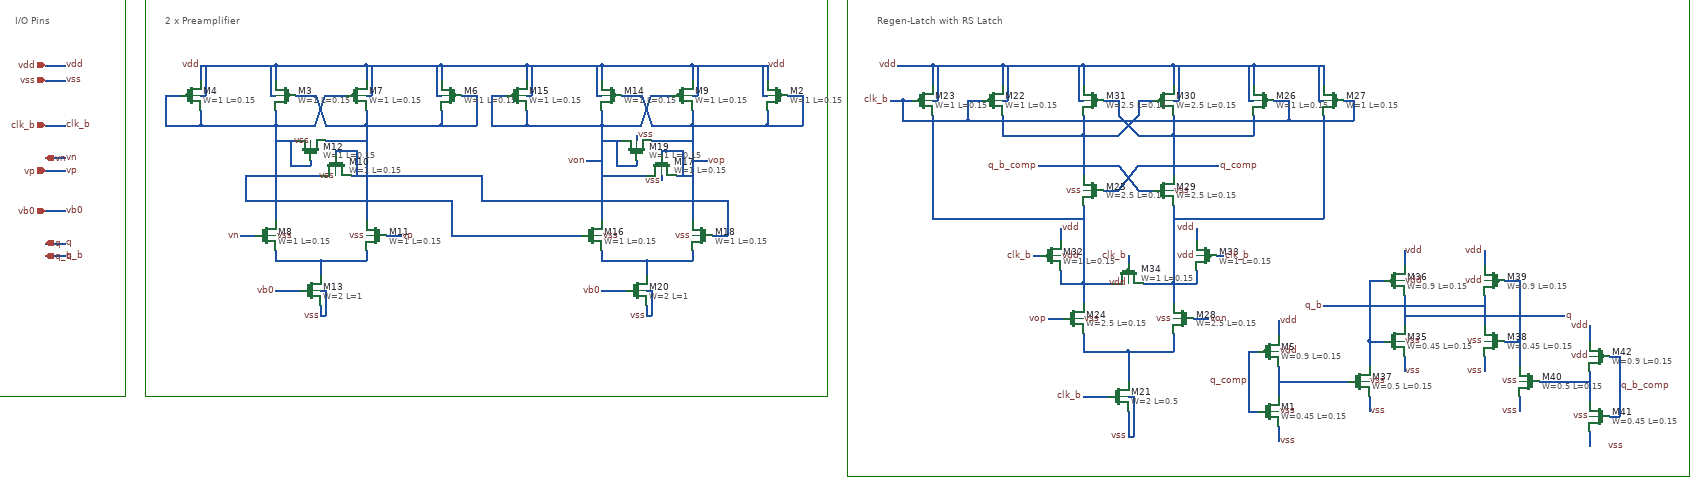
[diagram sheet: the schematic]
v {xschem version=3.4.6RC file_version=1.2
}
G {}
K {}
V {}
S {}
E {}
L 4 360 -1000 360 -200 {}
L 4 360 -1000 1720 -1000 {}
L 4 1720 -1000 1720 -200 {}
L 4 360 -200 1720 -200 {}
L 4 1760 -1000 1760 -40 {}
L 4 1760 -1000 3440 -1000 {}
L 4 3440 -1000 3440 -40 {}
L 4 1760 -40 3440 -40 {}
L 4 40 -1000 320 -1000 {}
L 4 40 -200 320 -200 {}
L 4 320 -1000 320 -200 {}
L 4 40 -1000 40 -200 {}
T {2 x Preamplifier
} 400 -960 0 0 0.4 0.4 {}
T {I/O Pins} 100 -960 0 0 0.4 0.4 {}
T {Regen-Latch with RS Latch} 1820 -960 0 0 0.4 0.4 {}
N 160 -860 200 -860 {
lab=vdd}
N 160 -830 200 -830 {
lab=vss}
N 160 -675 200 -675 {
lab=vn}
N 160 -650 200 -650 {
lab=vp}
N 160 -505 200 -505 {
lab=q}
N 160 -480 200 -480 {
lab=q_b}
N 160 -740 200 -740 {
lab=clk_b}
N 950 -770 950 -740 {lab=#net1}
N 800 -740 950 -740 {lab=#net1}
N 800 -770 800 -740 {lab=#net1}
N 800 -860 800 -830 {lab=vdd}
N 800 -860 950 -860 {lab=vdd}
N 950 -860 950 -830 {lab=vdd}
N 620 -770 620 -740 {lab=#net2}
N 470 -740 620 -740 {lab=#net2}
N 470 -770 470 -740 {lab=#net2}
N 470 -860 470 -830 {lab=vdd}
N 470 -860 620 -860 {lab=vdd}
N 620 -860 620 -830 {lab=vdd}
N 620 -860 800 -860 {lab=vdd}
N 400 -740 470 -740 {lab=#net2}
N 400 -800 400 -740 {lab=#net2}
N 400 -800 430 -800 {lab=#net2}
N 620 -740 700 -740 {lab=#net2}
N 720 -740 800 -740 {lab=#net1}
N 700 -800 720 -740 {lab=#net1}
N 660 -800 700 -800 {lab=#net1}
N 700 -740 720 -800 {lab=#net2}
N 720 -800 760 -800 {lab=#net2}
N 950 -740 1020 -740 {lab=#net1}
N 1020 -800 1020 -740 {lab=#net1}
N 990 -800 1020 -800 {lab=#net1}
N 800 -800 810 -800 {lab=vdd}
N 810 -860 810 -800 {lab=vdd}
N 940 -800 950 -800 {lab=vdd}
N 940 -860 940 -800 {lab=vdd}
N 610 -800 620 -800 {lab=vdd}
N 610 -860 610 -800 {lab=vdd}
N 470 -800 480 -800 {lab=vdd}
N 480 -860 480 -800 {lab=vdd}
N 800 -740 800 -650 {lab=#net1}
N 620 -740 620 -650 {lab=#net2}
N 620 -650 620 -610 {lab=#net2}
N 800 -650 800 -610 {lab=#net1}
N 800 -610 800 -550 {lab=#net1}
N 620 -610 620 -550 {lab=#net2}
N 740 -690 740 -680 {lab=#net1}
N 780 -690 780 -640 {lab=#net1}
N 690 -670 690 -660 {lab=#net2}
N 650 -660 690 -660 {lab=#net2}
N 650 -710 650 -660 {lab=#net2}
N 740 -690 780 -690 {lab=#net1}
N 620 -640 710 -640 {lab=#net2}
N 770 -640 800 -640 {lab=#net1}
N 720 -710 800 -710 {lab=#net1}
N 620 -710 660 -710 {lab=#net2}
N 710 -470 710 -440 {lab=#net3}
N 620 -470 710 -470 {lab=#net3}
N 620 -490 620 -470 {lab=#net3}
N 710 -470 800 -470 {lab=#net3}
N 800 -490 800 -470 {lab=#net3}
N 710 -380 710 -360 {lab=vss}
N 710 -410 720 -410 {lab=vss}
N 720 -410 720 -360 {lab=vss}
N 710 -360 720 -360 {lab=vss}
N 620 -410 670 -410 {lab=vb0}
N 550 -520 580 -520 {lab=vn}
N 840 -520 870 -520 {lab=vp}
N 1600 -770 1600 -740 {lab=vop}
N 1450 -740 1600 -740 {lab=vop}
N 1450 -770 1450 -740 {lab=vop}
N 1450 -860 1450 -830 {lab=vdd}
N 1450 -860 1600 -860 {lab=vdd}
N 1600 -860 1600 -830 {lab=vdd}
N 1270 -770 1270 -740 {lab=von}
N 1120 -740 1270 -740 {lab=von}
N 1120 -770 1120 -740 {lab=von}
N 1120 -860 1120 -830 {lab=vdd}
N 1120 -860 1270 -860 {lab=vdd}
N 1270 -860 1270 -830 {lab=vdd}
N 1270 -860 1450 -860 {lab=vdd}
N 1050 -740 1120 -740 {lab=von}
N 1050 -800 1050 -740 {lab=von}
N 1050 -800 1080 -800 {lab=von}
N 1270 -740 1350 -740 {lab=von}
N 1370 -740 1450 -740 {lab=vop}
N 1350 -800 1370 -740 {lab=vop}
N 1310 -800 1350 -800 {lab=vop}
N 1350 -740 1370 -800 {lab=von}
N 1370 -800 1410 -800 {lab=von}
N 1600 -740 1670 -740 {lab=vop}
N 1670 -800 1670 -740 {lab=vop}
N 1640 -800 1670 -800 {lab=vop}
N 1450 -800 1460 -800 {lab=vdd}
N 1460 -860 1460 -800 {lab=vdd}
N 1590 -800 1600 -800 {lab=vdd}
N 1590 -860 1590 -800 {lab=vdd}
N 1260 -800 1270 -800 {lab=vdd}
N 1260 -860 1260 -800 {lab=vdd}
N 1120 -800 1130 -800 {lab=vdd}
N 1130 -860 1130 -800 {lab=vdd}
N 1450 -740 1450 -650 {lab=vop}
N 1270 -740 1270 -650 {lab=von}
N 1270 -650 1270 -610 {lab=von}
N 1450 -650 1450 -610 {lab=vop}
N 1450 -610 1450 -550 {lab=vop}
N 1270 -610 1270 -550 {lab=von}
N 1390 -690 1390 -680 {lab=vop}
N 1430 -690 1430 -640 {lab=vop}
N 1340 -670 1340 -660 {lab=von}
N 1300 -660 1340 -660 {lab=von}
N 1300 -710 1300 -660 {lab=von}
N 1390 -690 1430 -690 {lab=vop}
N 1270 -640 1360 -640 {lab=von}
N 1420 -640 1450 -640 {lab=vop}
N 1370 -710 1450 -710 {lab=vop}
N 1270 -710 1310 -710 {lab=von}
N 1340 -720 1340 -710 {lab=vss}
N 1390 -640 1390 -630 {lab=vss}
N 1360 -470 1360 -440 {lab=#net4}
N 1270 -470 1360 -470 {lab=#net4}
N 1270 -490 1270 -470 {lab=#net4}
N 1360 -470 1450 -470 {lab=#net4}
N 1450 -490 1450 -470 {lab=#net4}
N 1360 -380 1360 -360 {lab=vss}
N 1360 -410 1370 -410 {lab=vss}
N 1370 -410 1370 -360 {lab=vss}
N 1360 -360 1370 -360 {lab=vss}
N 1270 -410 1320 -410 {lab=vb0}
N 1200 -520 1230 -520 {lab=#net2}
N 1490 -520 1520 -520 {lab=#net1}
N 1240 -670 1270 -670 {lab=von}
N 1450 -670 1480 -670 {lab=vop}
N 2070 -860 2070 -820 {
lab=vdd}
N 1930 -860 2070 -860 {
lab=vdd}
N 1930 -860 1930 -820 {
lab=vdd}
N 2000 -790 2030 -790 {
lab=clk_b}
N 2320 -170 2320 -120 {
lab=vss}
N 2230 -200 2280 -200 {
lab=clk_b}
N 2160 -355 2190 -355 {
lab=vop}
N 2000 -790 2000 -750 {
lab=clk_b}
N 1870 -750 2000 -750 {
lab=clk_b}
N 1870 -790 1870 -750 {
lab=clk_b}
N 2230 -860 2230 -820 {
lab=vdd}
N 2070 -860 2230 -860 {
lab=vdd}
N 2070 -760 2070 -720 {
lab=q_b_comp}
N 2230 -760 2230 -720 {
lab=q_b_comp}
N 2070 -720 2230 -720 {
lab=q_b_comp}
N 2230 -720 2230 -640 {
lab=q_b_comp}
N 2230 -325 2230 -290 {
lab=#net5}
N 2230 -290 2320 -290 {
lab=#net5}
N 1930 -555 2230 -555 {
lab=#net6}
N 1930 -760 1930 -555 {
lab=#net6}
N 2570 -860 2570 -820 {
lab=vdd}
N 2570 -860 2710 -860 {
lab=vdd}
N 2710 -860 2710 -820 {
lab=vdd}
N 2610 -790 2640 -790 {
lab=clk_b}
N 2450 -355 2480 -355 {
lab=von}
N 2640 -790 2640 -750 {
lab=clk_b}
N 2640 -750 2770 -750 {
lab=clk_b}
N 2770 -790 2770 -750 {
lab=clk_b}
N 2410 -860 2410 -820 {
lab=vdd}
N 2410 -860 2570 -860 {
lab=vdd}
N 2570 -760 2570 -720 {
lab=q_comp}
N 2410 -760 2410 -720 {
lab=q_comp}
N 2410 -720 2570 -720 {
lab=q_comp}
N 2410 -720 2410 -640 {
lab=q_comp}
N 2410 -325 2410 -290 {
lab=#net5}
N 2320 -290 2410 -290 {
lab=#net5}
N 2410 -555 2710 -555 {
lab=#net7}
N 2710 -760 2710 -555 {
lab=#net7}
N 2230 -860 2410 -860 {
lab=vdd}
N 2230 -720 2300 -720 {
lab=q_b_comp}
N 2340 -720 2410 -720 {
lab=q_comp}
N 2300 -760 2340 -720 {
lab=q_comp}
N 2300 -720 2340 -760 {
lab=q_b_comp}
N 2340 -790 2340 -760 {
lab=q_b_comp}
N 2340 -790 2370 -790 {
lab=q_b_comp}
N 2300 -790 2300 -760 {
lab=q_comp}
N 2270 -790 2300 -790 {
lab=q_comp}
N 2270 -610 2300 -610 {
lab=q_comp}
N 2300 -610 2340 -660 {
lab=q_comp}
N 2340 -610 2370 -610 {
lab=q_b_comp}
N 2300 -660 2340 -610 {
lab=q_b_comp}
N 2230 -660 2300 -660 {
lab=q_b_comp}
N 2340 -660 2410 -660 {
lab=q_comp}
N 2320 -290 2320 -230 {
lab=#net5}
N 1870 -790 1890 -790 {
lab=clk_b}
N 1845 -790 1870 -790 {
lab=clk_b}
N 1860 -860 1930 -860 {
lab=vdd}
N 2000 -750 2640 -750 {
lab=clk_b}
N 2750 -790 2770 -790 {
lab=clk_b}
N 2700 -790 2710 -790 {lab=vdd}
N 2700 -860 2700 -790 {lab=vdd}
N 2560 -790 2570 -790 {lab=vdd}
N 2560 -860 2560 -790 {lab=vdd}
N 2220 -790 2230 -790 {lab=vdd}
N 2220 -860 2220 -790 {lab=vdd}
N 2070 -790 2080 -790 {lab=vdd}
N 2080 -860 2080 -790 {lab=vdd}
N 1930 -790 1940 -790 {lab=vdd}
N 1940 -860 1940 -790 {lab=vdd}
N 2410 -790 2420 -790 {lab=vdd}
N 2420 -860 2420 -790 {lab=vdd}
N 2410 -660 2500 -660 {lab=q_comp}
N 2140 -660 2230 -660 {lab=q_b_comp}
N 2350 -425 2410 -425 {lab=#net7}
N 2230 -425 2290 -425 {lab=#net6}
N 2185 -425 2230 -425 {lab=#net6}
N 2230 -425 2230 -385 {lab=#net6}
N 2410 -425 2410 -385 {lab=#net7}
N 2230 -580 2230 -425 {lab=#net6}
N 2410 -580 2410 -425 {lab=#net7}
N 2455 -450 2455 -425 {lab=#net7}
N 2455 -535 2455 -510 {lab=vdd}
N 2185 -450 2185 -425 {lab=#net6}
N 2185 -535 2185 -510 {lab=vdd}
N 2410 -425 2455 -425 {lab=#net7}
N 2495 -480 2510 -480 {lab=clk_b}
N 2320 -480 2320 -465 {lab=clk_b}
N 2130 -480 2145 -480 {lab=clk_b}
N 160 -570 200 -570 {
lab=vb0}
N 950 -860 1120 -860 {lab=vdd}
N 800 -640 1030 -640 {lab=#net1}
N 1030 -640 1030 -590 {lab=#net1}
N 1520 -590 1520 -520 {lab=#net1}
N 1030 -590 1520 -590 {lab=#net1}
N 560 -640 620 -640 {lab=#net2}
N 560 -640 560 -590 {lab=#net2}
N 970 -520 1200 -520 {lab=#net2}
N 970 -590 970 -520 {lab=#net2}
N 560 -590 970 -590 {lab=#net2}
N 2320 -200 2330 -200 {lab=vss}
N 2330 -200 2330 -120 {lab=vss}
N 2320 -120 2330 -120 {lab=vss}
N 2800 -310 2800 -260 {lab=q_b}
N 2800 -200 2800 -170 {lab=vss}
N 2720 -230 2760 -230 {lab=#net8}
N 2870 -280 2870 -250 {lab=vss}
N 2800 -310 2830 -310 {lab=q_b}
N 2800 -430 2830 -430 {lab=q_b}
N 2870 -490 2870 -460 {lab=vdd}
N 3100 -310 3100 -260 {lab=q}
N 3100 -200 3100 -170 {lab=vss}
N 3140 -230 3180 -230 {lab=#net9}
N 3030 -280 3030 -250 {lab=vss}
N 3070 -310 3100 -310 {lab=q}
N 3070 -430 3100 -430 {lab=q}
N 3030 -490 3030 -460 {lab=vdd}
N 2800 -430 2800 -310 {lab=q_b}
N 3100 -430 3100 -310 {lab=q}
N 3030 -400 3030 -340 {lab=q_b}
N 2870 -400 2870 -340 {lab=q}
N 2870 -360 3100 -360 {lab=q}
N 2800 -380 3030 -380 {lab=q_b}
N 3100 -360 3190 -360 {lab=q}
N 2710 -380 2800 -380 {lab=q_b}
N 2620 -140 2620 -110 {lab=vss}
N 2620 -350 2620 -320 {lab=vdd}
N 2620 -260 2620 -200 {lab=#net8}
N 2560 -170 2580 -170 {lab=q_comp}
N 2560 -290 2560 -170 {lab=q_comp}
N 2560 -290 2580 -290 {lab=q_comp}
N 2620 -230 2720 -230 {lab=#net8}
N 3240 -130 3240 -100 {lab=vss}
N 3240 -340 3240 -310 {lab=vdd}
N 3240 -250 3240 -190 {lab=#net9}
N 3280 -160 3300 -160 {lab=q_b_comp}
N 3300 -280 3300 -160 {lab=q_b_comp}
N 3280 -280 3300 -280 {lab=q_b_comp}
N 3180 -230 3240 -230 {lab=#net9}
C {ipin.sym} 160 -650 0 0 {name=p25 lab=vp}
C {ipin.sym} 160 -675 2 1 {name=p8 lab=vn}
C {iopin.sym} 160 -860 2 0 {name=p2 lab=vdd}
C {lab_pin.sym} 200 -860 0 1 {name=p4 sig_type=std_logic lab=vdd
}
C {lab_pin.sym} 200 -675 0 1 {name=p11 sig_type=std_logic lab=vn
}
C {lab_pin.sym} 200 -650 0 1 {name=p12 sig_type=std_logic lab=vp
}
C {lab_pin.sym} 200 -830 0 1 {name=p13 sig_type=std_logic lab=vss
}
C {iopin.sym} 160 -830 2 0 {name=p14 lab=vss}
C {lab_pin.sym} 200 -505 0 1 {name=p20 sig_type=std_logic lab=q
}
C {lab_pin.sym} 200 -480 0 1 {name=p21 sig_type=std_logic lab=q_b
}
C {opin.sym} 160 -505 2 0 {name=p18 lab=q}
C {opin.sym} 160 -480 2 0 {name=p19 lab=q_b}
C {ipin.sym} 160 -740 0 0 {name=p28 lab=clk_b}
C {lab_pin.sym} 200 -740 0 1 {name=p7 sig_type=std_logic lab=clk_b
}
C {sky130_fd_pr/pfet_01v8.sym} 970 -800 0 1 {name=M6
W=1
L=0.15
nf=1
mult=1
ad="'int((nf+1)/2) * W/nf * 0.29'" 
pd="'2*int((nf+1)/2) * (W/nf + 0.29)'"
as="'int((nf+2)/2) * W/nf * 0.29'" 
ps="'2*int((nf+2)/2) * (W/nf + 0.29)'"
nrd="'0.29 / W'" nrs="'0.29 / W'"
sa=0 sb=0 sd=0
model=pfet_01v8
spiceprefix=X
}
C {sky130_fd_pr/pfet_01v8.sym} 780 -800 0 0 {name=M7
W=1
L=0.15
nf=1
mult=1
ad="'int((nf+1)/2) * W/nf * 0.29'" 
pd="'2*int((nf+1)/2) * (W/nf + 0.29)'"
as="'int((nf+2)/2) * W/nf * 0.29'" 
ps="'2*int((nf+2)/2) * (W/nf + 0.29)'"
nrd="'0.29 / W'" nrs="'0.29 / W'"
sa=0 sb=0 sd=0
model=pfet_01v8
spiceprefix=X
}
C {sky130_fd_pr/pfet_01v8.sym} 640 -800 0 1 {name=M3
W=1
L=0.15
nf=1
mult=1
ad="'int((nf+1)/2) * W/nf * 0.29'" 
pd="'2*int((nf+1)/2) * (W/nf + 0.29)'"
as="'int((nf+2)/2) * W/nf * 0.29'" 
ps="'2*int((nf+2)/2) * (W/nf + 0.29)'"
nrd="'0.29 / W'" nrs="'0.29 / W'"
sa=0 sb=0 sd=0
model=pfet_01v8
spiceprefix=X
}
C {sky130_fd_pr/pfet_01v8.sym} 450 -800 0 0 {name=M4
W=1
L=0.15
nf=1
mult=1
ad="'int((nf+1)/2) * W/nf * 0.29'" 
pd="'2*int((nf+1)/2) * (W/nf + 0.29)'"
as="'int((nf+2)/2) * W/nf * 0.29'" 
ps="'2*int((nf+2)/2) * (W/nf + 0.29)'"
nrd="'0.29 / W'" nrs="'0.29 / W'"
sa=0 sb=0 sd=0
model=pfet_01v8
spiceprefix=X
}
C {lab_pin.sym} 470 -860 2 1 {name=p9 sig_type=std_logic lab=vdd
}
C {sky130_fd_pr/nfet_01v8.sym} 600 -520 0 0 {name=M8
L=0.15
W=1
mult=1 nf=1
model=nfet_01v8
spiceprefix=X}
C {sky130_fd_pr/nfet_01v8.sym} 740 -660 1 0 {name=M10
L=0.15
W=1
mult=1 nf=1
model=nfet_01v8
spiceprefix=X}
C {sky130_fd_pr/nfet_01v8.sym} 820 -520 0 1 {name=M11
L=0.15
W=1
mult=1 nf=1
model=nfet_01v8
spiceprefix=X}
C {sky130_fd_pr/nfet_01v8.sym} 690 -690 3 0 {name=M12
L=0.15
W=1
mult=1 nf=1
model=nfet_01v8
spiceprefix=X}
C {sky130_fd_pr/nfet_01v8.sym} 690 -410 0 0 {name=M13
L=1
W=2
mult=1 nf=1
model=nfet_01v8
spiceprefix=X}
C {lab_pin.sym} 710 -360 2 1 {name=p17 sig_type=std_logic lab=vss
}
C {lab_pin.sym} 800 -520 2 1 {name=p22 sig_type=std_logic lab=vss
}
C {lab_pin.sym} 620 -520 0 1 {name=p23 sig_type=std_logic lab=vss
}
C {lab_pin.sym} 620 -410 2 1 {name=p24 sig_type=std_logic lab=vb0
}
C {lab_pin.sym} 550 -520 2 1 {name=p34 sig_type=std_logic lab=vn
}
C {lab_pin.sym} 870 -520 2 0 {name=p37 sig_type=std_logic lab=vp
}
C {lab_pin.sym} 2500 -660 0 1 {name=p39 sig_type=std_logic lab=q_comp
}
C {lab_pin.sym} 2140 -660 0 0 {name=p40 sig_type=std_logic lab=q_b_comp
}
C {sky130_fd_pr/pfet_01v8.sym} 1620 -800 0 1 {name=M2
W=1
L=0.15
nf=1
mult=1
ad="'int((nf+1)/2) * W/nf * 0.29'" 
pd="'2*int((nf+1)/2) * (W/nf + 0.29)'"
as="'int((nf+2)/2) * W/nf * 0.29'" 
ps="'2*int((nf+2)/2) * (W/nf + 0.29)'"
nrd="'0.29 / W'" nrs="'0.29 / W'"
sa=0 sb=0 sd=0
model=pfet_01v8
spiceprefix=X
}
C {sky130_fd_pr/pfet_01v8.sym} 1430 -800 0 0 {name=M9
W=1
L=0.15
nf=1
mult=1
ad="'int((nf+1)/2) * W/nf * 0.29'" 
pd="'2*int((nf+1)/2) * (W/nf + 0.29)'"
as="'int((nf+2)/2) * W/nf * 0.29'" 
ps="'2*int((nf+2)/2) * (W/nf + 0.29)'"
nrd="'0.29 / W'" nrs="'0.29 / W'"
sa=0 sb=0 sd=0
model=pfet_01v8
spiceprefix=X
}
C {sky130_fd_pr/pfet_01v8.sym} 1290 -800 0 1 {name=M14
W=1
L=0.15
nf=1
mult=1
ad="'int((nf+1)/2) * W/nf * 0.29'" 
pd="'2*int((nf+1)/2) * (W/nf + 0.29)'"
as="'int((nf+2)/2) * W/nf * 0.29'" 
ps="'2*int((nf+2)/2) * (W/nf + 0.29)'"
nrd="'0.29 / W'" nrs="'0.29 / W'"
sa=0 sb=0 sd=0
model=pfet_01v8
spiceprefix=X
}
C {sky130_fd_pr/pfet_01v8.sym} 1100 -800 0 0 {name=M15
W=1
L=0.15
nf=1
mult=1
ad="'int((nf+1)/2) * W/nf * 0.29'" 
pd="'2*int((nf+1)/2) * (W/nf + 0.29)'"
as="'int((nf+2)/2) * W/nf * 0.29'" 
ps="'2*int((nf+2)/2) * (W/nf + 0.29)'"
nrd="'0.29 / W'" nrs="'0.29 / W'"
sa=0 sb=0 sd=0
model=pfet_01v8
spiceprefix=X
}
C {lab_pin.sym} 1600 -860 0 1 {name=p41 sig_type=std_logic lab=vdd
}
C {sky130_fd_pr/nfet_01v8.sym} 1250 -520 0 0 {name=M16
L=0.15
W=1
mult=1 nf=1
model=nfet_01v8
spiceprefix=X}
C {sky130_fd_pr/nfet_01v8.sym} 1390 -660 1 0 {name=M17
L=0.15
W=1
mult=1 nf=1
model=nfet_01v8
spiceprefix=X}
C {sky130_fd_pr/nfet_01v8.sym} 1470 -520 0 1 {name=M18
L=0.15
W=1
mult=1 nf=1
model=nfet_01v8
spiceprefix=X}
C {sky130_fd_pr/nfet_01v8.sym} 1340 -690 3 0 {name=M19
L=0.15
W=1
mult=1 nf=1
model=nfet_01v8
spiceprefix=X}
C {lab_pin.sym} 1390 -630 1 1 {name=p43 sig_type=std_logic lab=vss
}
C {lab_pin.sym} 1340 -720 0 1 {name=p44 sig_type=std_logic lab=vss
}
C {sky130_fd_pr/nfet_01v8.sym} 1340 -410 0 0 {name=M20
L=1
W=2
mult=1 nf=1
model=nfet_01v8
spiceprefix=X}
C {lab_pin.sym} 1360 -360 2 1 {name=p45 sig_type=std_logic lab=vss
}
C {lab_pin.sym} 1450 -520 2 1 {name=p46 sig_type=std_logic lab=vss
}
C {lab_pin.sym} 1270 -520 0 1 {name=p47 sig_type=std_logic lab=vss
}
C {lab_pin.sym} 1270 -410 2 1 {name=p48 sig_type=std_logic lab=vb0
}
C {lab_pin.sym} 1240 -670 2 1 {name=p50 sig_type=std_logic lab=von
}
C {lab_pin.sym} 1480 -670 2 0 {name=p51 sig_type=std_logic lab=vop
}
C {sky130_fd_pr/nfet_01v8.sym} 2300 -200 0 0 {name=M21
W=2
L=0.5
nf=1
mult=1
ad="'int((nf+1)/2) * W/nf * 0.29'" 
pd="'2*int((nf+1)/2) * (W/nf + 0.29)'"
as="'int((nf+2)/2) * W/nf * 0.29'" 
ps="'2*int((nf+2)/2) * (W/nf + 0.29)'"
nrd="'0.29 / W'" nrs="'0.29 / W'"
sa=0 sb=0 sd=0
model=nfet_01v8
spiceprefix=X
}
C {sky130_fd_pr/pfet_01v8.sym} 2050 -790 0 0 {name=M22
W=1
L=0.15
nf=1
mult=1
ad="'int((nf+1)/2) * W/nf * 0.29'" 
pd="'2*int((nf+1)/2) * (W/nf + 0.29)'"
as="'int((nf+2)/2) * W/nf * 0.29'" 
ps="'2*int((nf+2)/2) * (W/nf + 0.29)'"
nrd="'0.29 / W'" nrs="'0.29 / W'"
sa=0 sb=0 sd=0
model=pfet_01v8
spiceprefix=X
}
C {sky130_fd_pr/pfet_01v8.sym} 1910 -790 0 0 {name=M23
W=1
L=0.15
nf=1
mult=1
ad="'int((nf+1)/2) * W/nf * 0.29'" 
pd="'2*int((nf+1)/2) * (W/nf + 0.29)'"
as="'int((nf+2)/2) * W/nf * 0.29'" 
ps="'2*int((nf+2)/2) * (W/nf + 0.29)'"
nrd="'0.29 / W'" nrs="'0.29 / W'"
sa=0 sb=0 sd=0
model=pfet_01v8
spiceprefix=X
}
C {sky130_fd_pr/nfet_01v8.sym} 2210 -355 0 0 {name=M24
W=2.5
L=0.15
nf=4
mult=1
ad="'int((nf+1)/2) * W/nf * 0.29'" 
pd="'2*int((nf+1)/2) * (W/nf + 0.29)'"
as="'int((nf+2)/2) * W/nf * 0.29'" 
ps="'2*int((nf+2)/2) * (W/nf + 0.29)'"
nrd="'0.29 / W'" nrs="'0.29 / W'"
sa=0 sb=0 sd=0
model=nfet_01v8
spiceprefix=X
}
C {sky130_fd_pr/nfet_01v8.sym} 2250 -610 0 1 {name=M25
W=2.5
L=0.15
nf=4
mult=1
ad="'int((nf+1)/2) * W/nf * 0.29'" 
pd="'2*int((nf+1)/2) * (W/nf + 0.29)'"
as="'int((nf+2)/2) * W/nf * 0.29'" 
ps="'2*int((nf+2)/2) * (W/nf + 0.29)'"
nrd="'0.29 / W'" nrs="'0.29 / W'"
sa=0 sb=0 sd=0
model=nfet_01v8
spiceprefix=X
}
C {lab_pin.sym} 2230 -610 0 0 {name=p52 sig_type=std_logic lab=vss
}
C {lab_pin.sym} 2230 -355 0 1 {name=p53 sig_type=std_logic lab=vss
}
C {sky130_fd_pr/pfet_01v8.sym} 2590 -790 0 1 {name=M26
W=1
L=0.15
nf=1
mult=1
ad="'int((nf+1)/2) * W/nf * 0.29'" 
pd="'2*int((nf+1)/2) * (W/nf + 0.29)'"
as="'int((nf+2)/2) * W/nf * 0.29'" 
ps="'2*int((nf+2)/2) * (W/nf + 0.29)'"
nrd="'0.29 / W'" nrs="'0.29 / W'"
sa=0 sb=0 sd=0
model=pfet_01v8
spiceprefix=X
}
C {sky130_fd_pr/pfet_01v8.sym} 2730 -790 0 1 {name=M27
W=1
L=0.15
nf=1
mult=1
ad="'int((nf+1)/2) * W/nf * 0.29'" 
pd="'2*int((nf+1)/2) * (W/nf + 0.29)'"
as="'int((nf+2)/2) * W/nf * 0.29'" 
ps="'2*int((nf+2)/2) * (W/nf + 0.29)'"
nrd="'0.29 / W'" nrs="'0.29 / W'"
sa=0 sb=0 sd=0
model=pfet_01v8
spiceprefix=X
}
C {sky130_fd_pr/nfet_01v8.sym} 2430 -355 0 1 {name=M28
W=2.5
L=0.15
nf=4
mult=1
ad="'int((nf+1)/2) * W/nf * 0.29'" 
pd="'2*int((nf+1)/2) * (W/nf + 0.29)'"
as="'int((nf+2)/2) * W/nf * 0.29'" 
ps="'2*int((nf+2)/2) * (W/nf + 0.29)'"
nrd="'0.29 / W'" nrs="'0.29 / W'"
sa=0 sb=0 sd=0
model=nfet_01v8
spiceprefix=X
}
C {sky130_fd_pr/nfet_01v8.sym} 2390 -610 0 0 {name=M29
W=2.5
L=0.15
nf=4
mult=1
ad="'int((nf+1)/2) * W/nf * 0.29'" 
pd="'2*int((nf+1)/2) * (W/nf + 0.29)'"
as="'int((nf+2)/2) * W/nf * 0.29'" 
ps="'2*int((nf+2)/2) * (W/nf + 0.29)'"
nrd="'0.29 / W'" nrs="'0.29 / W'"
sa=0 sb=0 sd=0
model=nfet_01v8
spiceprefix=X
}
C {lab_pin.sym} 2410 -610 0 1 {name=p64 sig_type=std_logic lab=vss
}
C {lab_pin.sym} 2410 -355 0 0 {name=p65 sig_type=std_logic lab=vss
}
C {sky130_fd_pr/pfet_01v8.sym} 2390 -790 0 0 {name=M30
W=2.5
L=0.15
nf=1
mult=1
ad="'int((nf+1)/2) * W/nf * 0.29'" 
pd="'2*int((nf+1)/2) * (W/nf + 0.29)'"
as="'int((nf+2)/2) * W/nf * 0.29'" 
ps="'2*int((nf+2)/2) * (W/nf + 0.29)'"
nrd="'0.29 / W'" nrs="'0.29 / W'"
sa=0 sb=0 sd=0
model=pfet_01v8
spiceprefix=X
}
C {sky130_fd_pr/pfet_01v8.sym} 2250 -790 0 1 {name=M31
W=2.5
L=0.15
nf=1
mult=1
ad="'int((nf+1)/2) * W/nf * 0.29'" 
pd="'2*int((nf+1)/2) * (W/nf + 0.29)'"
as="'int((nf+2)/2) * W/nf * 0.29'" 
ps="'2*int((nf+2)/2) * (W/nf + 0.29)'"
nrd="'0.29 / W'" nrs="'0.29 / W'"
sa=0 sb=0 sd=0
model=pfet_01v8
spiceprefix=X
}
C {lab_pin.sym} 1860 -860 2 1 {name=p59 sig_type=std_logic lab=vdd
}
C {lab_pin.sym} 1845 -790 2 1 {name=p60 sig_type=std_logic lab=clk_b
}
C {lab_pin.sym} 2320 -120 2 1 {name=p54 sig_type=std_logic lab=vss
}
C {lab_pin.sym} 2160 -355 2 1 {name=p55 sig_type=std_logic lab=vop
}
C {lab_pin.sym} 2480 -355 2 0 {name=p56 sig_type=std_logic lab=von
}
C {sky130_fd_pr/pfet_01v8.sym} 2165 -480 0 0 {name=M32
W=1
L=0.15
nf=1
mult=1
ad="'int((nf+1)/2) * W/nf * 0.29'" 
pd="'2*int((nf+1)/2) * (W/nf + 0.29)'"
as="'int((nf+2)/2) * W/nf * 0.29'" 
ps="'2*int((nf+2)/2) * (W/nf + 0.29)'"
nrd="'0.29 / W'" nrs="'0.29 / W'"
sa=0 sb=0 sd=0
model=pfet_01v8
spiceprefix=X
}
C {sky130_fd_pr/pfet_01v8.sym} 2475 -480 0 1 {name=M33
W=1
L=0.15
nf=1
mult=1
ad="'int((nf+1)/2) * W/nf * 0.29'" 
pd="'2*int((nf+1)/2) * (W/nf + 0.29)'"
as="'int((nf+2)/2) * W/nf * 0.29'" 
ps="'2*int((nf+2)/2) * (W/nf + 0.29)'"
nrd="'0.29 / W'" nrs="'0.29 / W'"
sa=0 sb=0 sd=0
model=pfet_01v8
spiceprefix=X
}
C {sky130_fd_pr/pfet_01v8.sym} 2320 -445 3 1 {name=M34
W=1
L=0.15
nf=1
mult=1
ad="'int((nf+1)/2) * W/nf * 0.29'" 
pd="'2*int((nf+1)/2) * (W/nf + 0.29)'"
as="'int((nf+2)/2) * W/nf * 0.29'" 
ps="'2*int((nf+2)/2) * (W/nf + 0.29)'"
nrd="'0.29 / W'" nrs="'0.29 / W'"
sa=0 sb=0 sd=0
model=pfet_01v8
spiceprefix=X
}
C {lab_pin.sym} 2185 -480 0 1 {name=p61 sig_type=std_logic lab=vdd
}
C {lab_pin.sym} 2320 -425 1 1 {name=p62 sig_type=std_logic lab=vdd
}
C {lab_pin.sym} 2455 -480 2 1 {name=p63 sig_type=std_logic lab=vdd
}
C {lab_pin.sym} 2455 -535 2 1 {name=p66 sig_type=std_logic lab=vdd
}
C {lab_pin.sym} 2185 -535 2 0 {name=p67 sig_type=std_logic lab=vdd
}
C {lab_pin.sym} 2130 -480 2 1 {name=p68 sig_type=std_logic lab=clk_b
}
C {lab_pin.sym} 2320 -480 3 1 {name=p69 sig_type=std_logic lab=clk_b
}
C {lab_pin.sym} 2510 -480 0 1 {name=p70 sig_type=std_logic lab=clk_b
}
C {lab_pin.sym} 2230 -200 2 1 {name=p71 sig_type=std_logic lab=clk_b
}
C {ipin.sym} 160 -570 0 0 {name=p1 lab=vb0}
C {lab_pin.sym} 200 -570 0 1 {name=p5 sig_type=std_logic lab=vb0

}
C {lab_pin.sym} 740 -640 1 1 {name=p15 sig_type=std_logic lab=vss
}
C {lab_pin.sym} 690 -710 3 1 {name=p16 sig_type=std_logic lab=vss
}
C {title.sym} 200 -50 0 0 {name=l1 author="Refik Yalcin"}
C {sky130_fd_pr/nfet_01v8.sym} 2850 -310 0 0 {name=M35
L=0.15
W=0.45
mult=1 nf=1
model=nfet_01v8
spiceprefix=X}
C {sky130_fd_pr/pfet_01v8.sym} 2850 -430 0 0 {name=M36
W=0.9
L=0.15
nf=1
mult=1
ad="'int((nf+1)/2) * W/nf * 0.29'" 
pd="'2*int((nf+1)/2) * (W/nf + 0.29)'"
as="'int((nf+2)/2) * W/nf * 0.29'" 
ps="'2*int((nf+2)/2) * (W/nf + 0.29)'"
nrd="'0.29 / W'" nrs="'0.29 / W'"
sa=0 sb=0 sd=0
model=pfet_01v8
spiceprefix=X
}
C {lab_pin.sym} 2870 -430 2 0 {name=p3 sig_type=std_logic lab=vdd
}
C {lab_pin.sym} 2870 -310 2 0 {name=p6 sig_type=std_logic lab=vss

}
C {sky130_fd_pr/nfet_01v8.sym} 2780 -230 0 0 {name=M37
L=0.15
W=0.5
mult=1 nf=1
model=nfet_01v8
spiceprefix=X}
C {lab_pin.sym} 2800 -230 2 0 {name=p10 sig_type=std_logic lab=vss

}
C {lab_pin.sym} 2800 -170 2 0 {name=p26 sig_type=std_logic lab=vss

}
C {lab_pin.sym} 2560 -230 2 1 {name=p27 sig_type=std_logic lab=q_comp}
C {lab_pin.sym} 2870 -250 2 0 {name=p29 sig_type=std_logic lab=vss

}
C {lab_pin.sym} 2870 -490 2 0 {name=p36 sig_type=std_logic lab=vdd
}
C {sky130_fd_pr/nfet_01v8.sym} 3050 -310 0 1 {name=M38
L=0.15
W=0.45
mult=1 nf=1
model=nfet_01v8
spiceprefix=X}
C {sky130_fd_pr/pfet_01v8.sym} 3050 -430 0 1 {name=M39
W=0.9
L=0.15
nf=1
mult=1
ad="'int((nf+1)/2) * W/nf * 0.29'" 
pd="'2*int((nf+1)/2) * (W/nf + 0.29)'"
as="'int((nf+2)/2) * W/nf * 0.29'" 
ps="'2*int((nf+2)/2) * (W/nf + 0.29)'"
nrd="'0.29 / W'" nrs="'0.29 / W'"
sa=0 sb=0 sd=0
model=pfet_01v8
spiceprefix=X
}
C {lab_pin.sym} 3030 -430 2 1 {name=p38 sig_type=std_logic lab=vdd
}
C {lab_pin.sym} 3030 -310 2 1 {name=p42 sig_type=std_logic lab=vss

}
C {sky130_fd_pr/nfet_01v8.sym} 3120 -230 0 1 {name=M40
L=0.15
W=0.5
mult=1 nf=1
model=nfet_01v8
spiceprefix=X}
C {lab_pin.sym} 3100 -230 2 1 {name=p49 sig_type=std_logic lab=vss

}
C {lab_pin.sym} 3100 -170 2 1 {name=p72 sig_type=std_logic lab=vss

}
C {lab_pin.sym} 3300 -220 2 0 {name=p73 sig_type=std_logic lab=q_b_comp}
C {lab_pin.sym} 3030 -250 2 1 {name=p74 sig_type=std_logic lab=vss

}
C {lab_pin.sym} 3030 -490 2 1 {name=p75 sig_type=std_logic lab=vdd
}
C {lab_pin.sym} 3190 -360 0 1 {name=p76 sig_type=std_logic lab=q
}
C {lab_pin.sym} 2710 -380 2 1 {name=p77 sig_type=std_logic lab=q_b
}
C {sky130_fd_pr/nfet_01v8.sym} 2600 -170 0 0 {name=M1
L=0.15
W=0.45
mult=1 nf=1
model=nfet_01v8
spiceprefix=X}
C {sky130_fd_pr/pfet_01v8.sym} 2600 -290 0 0 {name=M5
W=0.9
L=0.15
nf=1
mult=1
ad="'int((nf+1)/2) * W/nf * 0.29'" 
pd="'2*int((nf+1)/2) * (W/nf + 0.29)'"
as="'int((nf+2)/2) * W/nf * 0.29'" 
ps="'2*int((nf+2)/2) * (W/nf + 0.29)'"
nrd="'0.29 / W'" nrs="'0.29 / W'"
sa=0 sb=0 sd=0
model=pfet_01v8
spiceprefix=X
}
C {lab_pin.sym} 2620 -290 2 0 {name=p30 sig_type=std_logic lab=vdd
}
C {lab_pin.sym} 2620 -170 2 0 {name=p31 sig_type=std_logic lab=vss

}
C {lab_pin.sym} 2620 -110 2 0 {name=p32 sig_type=std_logic lab=vss

}
C {lab_pin.sym} 2620 -350 2 0 {name=p33 sig_type=std_logic lab=vdd
}
C {sky130_fd_pr/nfet_01v8.sym} 3260 -160 0 1 {name=M41
L=0.15
W=0.45
mult=1 nf=1
model=nfet_01v8
spiceprefix=X}
C {sky130_fd_pr/pfet_01v8.sym} 3260 -280 0 1 {name=M42
W=0.9
L=0.15
nf=1
mult=1
ad="'int((nf+1)/2) * W/nf * 0.29'" 
pd="'2*int((nf+1)/2) * (W/nf + 0.29)'"
as="'int((nf+2)/2) * W/nf * 0.29'" 
ps="'2*int((nf+2)/2) * (W/nf + 0.29)'"
nrd="'0.29 / W'" nrs="'0.29 / W'"
sa=0 sb=0 sd=0
model=pfet_01v8
spiceprefix=X
}
C {lab_pin.sym} 3240 -280 2 1 {name=p78 sig_type=std_logic lab=vdd
}
C {lab_pin.sym} 3240 -160 2 1 {name=p79 sig_type=std_logic lab=vss

}
C {lab_pin.sym} 3310 -100 2 1 {name=p80 sig_type=std_logic lab=vss

}
C {lab_pin.sym} 3240 -340 2 1 {name=p81 sig_type=std_logic lab=vdd
}
